VERSION 5.8 ;
BUSBITCHARS "[]" ;
DIVIDERCHAR "/" ;
UNITS
    DATABASE MICRONS 1000 ;
END UNITS

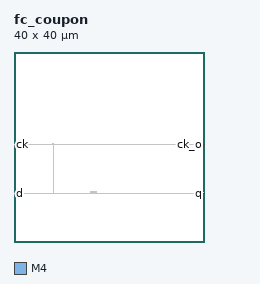
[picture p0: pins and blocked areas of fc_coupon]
MACRO fc_coupon
  FOREIGN fc_coupon 0 0 ;
  CLASS BLOCK ;
  SIZE 40 BY 40 ;
  PIN VDD
    USE POWER ;
    DIRECTION INOUT ;
  END VDD
  PIN VSS
    USE GROUND ;
    DIRECTION INOUT ;
  END VSS
  PIN ck
    DIRECTION INPUT ;
    USE SIGNAL ;
    PORT
      LAYER M4 ;
        RECT  0 20.496 0.084 20.52 ;
    END
  END ck
  PIN ck_o
    DIRECTION OUTPUT ;
    USE SIGNAL ;
    PORT
      LAYER M4 ;
        RECT  39.916 20.496 40 20.52 ;
    END
  END ck_o
  PIN d
    DIRECTION INPUT ;
    USE SIGNAL ;
    PORT
      LAYER M4 ;
        RECT  0 10.272 0.084 10.296 ;
    END
  END d
  PIN q
    DIRECTION OUTPUT ;
    USE SIGNAL ;
    PORT
      LAYER M4 ;
        RECT  39.916 10.272 40 10.296 ;
    END
  END q
  OBS
    LAYER RVTN ;
     RECT  16.2 10.26 17.28 10.395 ;
     RECT  8.1 20.52 8.37 20.655 ;
    LAYER RVTP ;
     RECT  16.2 10.395 17.28 10.53 ;
     RECT  8.1 20.655 8.37 20.79 ;
    LAYER M1 ;
     RECT  16.2 10.251 17.28 10.539 ;
     RECT  8.1 20.511 8.37 20.799 ;
    LAYER M2 ;
     RECT  7.411 10.251 8.275 10.269 ;
     RECT  8.131 20.556 8.555 20.574 ;
     RECT  8.275 10.251 16.219 10.314 ;
     RECT  16.219 10.251 16.375 10.422 ;
     RECT  16.375 10.251 16.475 10.458 ;
     RECT  16.475 10.404 16.727 10.458 ;
     RECT  16.727 10.404 17.213 10.422 ;
     RECT  17.239 10.296 39.911 10.314 ;
    LAYER M3 ;
     RECT  7.416 10.246 7.434 10.301 ;
     RECT  16.452 10.246 16.47 10.319 ;
     RECT  39.888 10.267 39.906 10.319 ;
     RECT  8.28 10.291 8.298 20.491 ;
     RECT  8.136 20.491 8.55 20.579 ;
    LAYER M4 ;
     RECT  0.06 10.272 7.445 10.296 ;
     RECT  39.877 10.272 39.948 10.296 ;
     RECT  0.06 20.496 39.948 20.52 ;
  END
END fc_coupon
END LIBRARY
